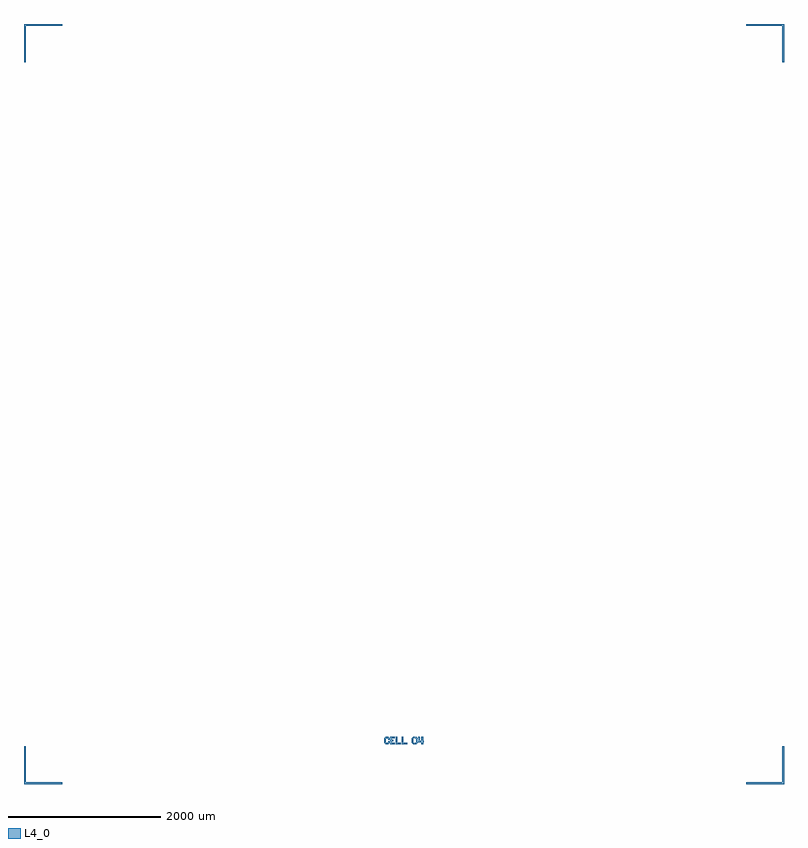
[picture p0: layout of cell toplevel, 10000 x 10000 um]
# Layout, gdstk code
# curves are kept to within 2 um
import gdstk
lib = gdstk.Library(unit=1e-6, precision=1e-09)
def P(c, l, *ps):  # polygons
    for p in ps: c.add(gdstk.Polygon(p, *l))
L4_0 = (4, 0)

toplevel = lib.new_cell('toplevel')
P(toplevel, L4_0, [(5000,5000),(5000,4500),(4980,4500),(4980,4980),(4500,4980),(4500,5000)],
  [(-5000,5000),(-5000,4500),(-4980,4500),(-4980,4980),(-4500,4980),(-4500,5000)],
  [(5000,-5000),(5000,-4500),(4980,-4500),(4980,-4980),(4500,-4980),(4500,-5000)],
  [(-5000,-5000),(-5000,-4500),(-4980,-4500),(-4980,-4980),(-4500,-4980),(-4500,-5000)],
  [(-240,-4480),(-260,-4460),(-260,-4400),(-240,-4380),(-210,-4380),(-190,-4400),(-190,-4420),(-210,-4420),(-210,-4410),(-220,-4400),(-230,-4400),(-240,-4410),(-240,-4450),(-230,-4460),(-220,-4460),(-210,-4450),(-210,-4440),(-190,-4440),(-190,-4460),(-210,-4480)],
  [(-120,-4380),(-120,-4400),(-160,-4400),(-160,-4420),(-140,-4420),(-140,-4440),(-160,-4440),(-160,-4460),(-120,-4460),(-120,-4480),(-180,-4480),(-180,-4380),(-120,-4380)],
  [(-110,-4380),(-90,-4380),(-90,-4460),(-40,-4460),(-40,-4480),(-110,-4480),(-110,-4380)],
  [(-30,-4380),(-10,-4380),(-10,-4460),(40,-4460),(40,-4480),(-30,-4480),(-30,-4380)],
  [(130,-4400),(120,-4410),(120,-4450),(130,-4460),(125,-4480),(120,-4480),(100,-4460),(100,-4400),(120,-4380),(143,-4380),(138,-4400),(130,-4400)],
  [(150,-4460),(160,-4450),(160,-4410),(150,-4400),(155,-4380),(160,-4380),(180,-4400),(180,-4460),(160,-4480),(137,-4480),(142,-4460),(150,-4460)],
  [(260,-4430),(260,-4450),(250,-4450),(250,-4480),(230,-4480),(230,-4450),(190,-4450),(190,-4380),(210,-4380),(210,-4430),(230,-4430),(230,-4380),(250,-4380),(250,-4430),(260,-4430)])

lib.write_gds('toplevel.gds')
